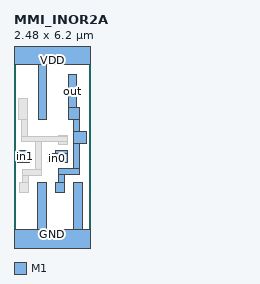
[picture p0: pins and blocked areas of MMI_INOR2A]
MACRO MMI_INOR2A
	CLASS CORE ;
	FOREIGN MMI_INOR2A 0 0 ;
	SIZE 2.48 BY 6.2 ;
	SYMMETRY X Y ;
	SITE CORE1 ;
	PIN out
		DIRECTION output ;
		USE SIGNAL ;
		PORT
			LAYER M1 ;
			RECT 1.765 4.385 2.045 5.455 ;
			LAYER M1 ;
			RECT 1.765 3.985 2.145 4.385 ;
			LAYER M1 ;
			RECT 1.95 3.6 2.145 3.985 ;
			LAYER M1 ;
			RECT 1.95 3.22 2.36 3.6 ;
			LAYER M1 ;
			RECT 1.95 2.39 2.145 3.22 ;
			LAYER M1 ;
			RECT 1.455 2.195 2.145 2.39 ;
			LAYER M1 ;
			RECT 1.455 1.945 1.645 2.195 ;
			LAYER M1 ;
			RECT 1.365 1.63 1.645 1.945 ;
		END
		AntennaDiffArea 0.7777 ;
	END out
	PIN in1
		DIRECTION input ;
		USE SIGNAL ;
		PORT
			LAYER M1 ;
			RECT 0.12 2.6 0.5 2.98 ;
		END
		AntennaGateArea 0.17325 ;
	END in1
	PIN GND
		DIRECTION inout ;
		USE GROUND ;
		PORT
			LAYER M1 ;
			RECT 0.775 0.42 1.055 1.945 ;
			LAYER M1 ;
			RECT 1.955 0.42 2.235 1.945 ;
			LAYER M1 ;
			RECT 0 -0.42 2.48 0.42 ;
		END
	END GND
	PIN VDD
		DIRECTION inout ;
		USE POWER ;
		PORT
			LAYER M1 ;
			RECT 0 5.78 2.48 6.62 ;
			LAYER M1 ;
			RECT 0.795 3.985 1.075 5.78 ;
		END
	END VDD
	PIN in0
		DIRECTION input ;
		USE SIGNAL ;
		PORT
			LAYER M1 ;
			RECT 1.36 2.885 1.74 2.98 ;
			LAYER M1 ;
			RECT 1.125 2.88 1.74 2.885 ;
			LAYER M1 ;
			RECT 1.095 2.6 1.74 2.88 ;
		END
		AntennaGateArea 0.28875 ;
	END in0
	OBS
		LAYER M1 ;
		RECT 0.16 3.985 0.44 4.685 ;
		LAYER M1 ;
		RECT 0.25 3.455 0.44 3.985 ;
		LAYER M1 ;
		RECT 1.45 3.455 1.73 3.46 ;
		LAYER M1 ;
		RECT 0.25 3.265 1.73 3.455 ;
		LAYER M1 ;
		RECT 0.7 2.37 0.89 3.265 ;
		LAYER M1 ;
		RECT 1.45 3.18 1.73 3.265 ;
		LAYER M1 ;
		RECT 0.275 2.175 0.89 2.37 ;
		LAYER M1 ;
		RECT 0.275 1.945 0.465 2.175 ;
		LAYER M1 ;
		RECT 0.185 1.63 0.465 1.945 ;
	END
END MMI_INOR2A
